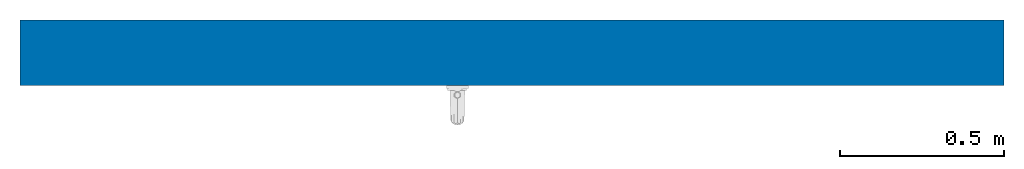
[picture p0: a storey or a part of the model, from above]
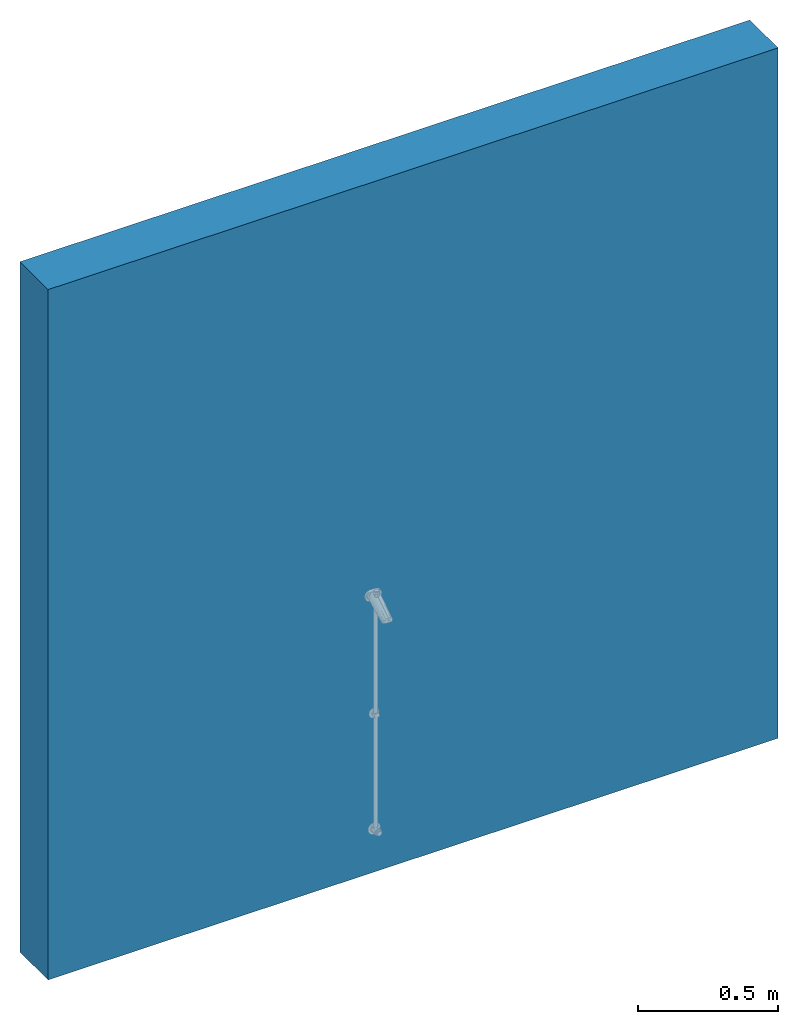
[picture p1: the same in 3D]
Properties of the parts of a building model (IFC2X3)

# File
Description: ViewDefinition [CoordinationView]
File name: Project Number
Time: 2016-08-02T11:35:12
Written by: Autodesk Revit Architecture 2011 - 1.0
Made in: 20100326_1700(x64)

# IfcProject, Project Number
Phase: Project Status

# IfcSite, Default
RefLatitude: 42, 21, 30, 344238; RefLongitude: -71, -3, -35, -194702; RefElevation: 0 mm

# IfcBuilding
Pset_BuildingCommon - NumberOfStoreys: 1
PSet_Revit_Other - Project Issue Date: Issue Date; Project Status: Project Status; Client Name: Owner; Project Address: Enter address here; Project Name: Project Name; Project Number: Project Number

# IfcBuildingStorey, Level 1
Elevation: 0 mm
PSet_Revit_Identity Data - Name: Level 1
PSet_Revit_Constraints - Elevation: 0 mm
PSet_Revit_Type_Graphics - Line Weight: 1; Color: 0; Line Pattern: Centre; Symbol: M_Level Head - Circle; Symbol at End 1 Default: no; Symbol at End 2 Default: yes
PSet_Revit_Type_Constraints - Elevation Base: 0
PSet_Revit_Type_Dimensions - Automatic Room Computation Height: no; Computation Height: 1200 mm

# IfcBuildingElementProxy: Type 1, 714000:Type 1:Type 1:158573
In: Level 1
PSet_Revit_Constraints - Level: Level 1; Elevation: 174.5 mm
PSet_Revit_Mechanical - System Type: Domestic Hot Water; System Name: Default Domestic Hot Water (Polantis_Production)
PSet_Revit_Identity Data - Mark: 9
PSet_Revit_Phasing - Phase Created: New Construction
PSet_Revit_Type_Identity Data - URL: www.delabie.fr; Type Comments: Ensemble de douche temporisé; Technologie: Temporisée; Référence: 714000; Raccordement: M1/2"; Model: SPORTING; Manufacturer: DELABIE; Lien notice d'installation: www.delabie.fr/produits/714000; Lien fiche produit: www.delabie.fr/produits/714000; Lien certification: www.delabie.fr/produits/714000; Lien CCTP: www.delabie.fr/produits/714000; Hauteur: 1015 mm; Finition: Laiton massif chromé; Famille de produits: Douche; Débit l/s: 0.10 l/s à 3 bar; Débit l/min: 6 l/min à 3 bar; Description: DELABIE, fabricant français, est le leader européen de l'équipement sanitaire pour les établissements recevant du public. Robinetteries, solutions pour personnes à mobilité réduite, appareils sanitaires, destinés aux écoles, lieux de loisirs, bureaux, hôpitaux, aéroports, ...; Descriptif: Ensemble de douche temporisé à poser en applique : Colonne de liaison Ø 16 et collier renforcés. Robinet temporisé SPORTING M1/2" pour alimentation par le haut en eau mitigée. Déclenchement souple. Temporisation ~30 sec. Débit 6 l/min à 3 bar. Pomme de douche chromée, inviolable à diffuseur antitartre avec régulateur automatique de débit. Bouton amorceur. Fixations par vis inox fournies. Corps en laiton massif chromé. Clapet antiretour et filtre intégrés.
PSet_Revit_Type_Dimensions - Radius: 10.3 mm

# IfcWallStandardCase: Basic Wall:Generic - 200mm:398, Basic Wall:Generic - 200mm:127590
In: Level 1
Material: Default Wall 200 mm
Pset_WallCommon - Reference: Basic Wall:Generic - 200mm; LoadBearing: no; ExtendToStructure: no; IsExternal: yes
PSet_Revit_Constraints - Location Line: 0; Base Constraint: Level 1; Base Offset: 0 mm; Base is Attached: no; Base Extension Distance: 0 mm; Unconnected Height: 3000 mm; Top Offset: 0 mm; Top is Attached: no; Top Extension Distance: 0 mm; Room Bounding: yes; Related to Mass: no
PSet_Revit_Phasing - Phase Created: New Construction
PSet_Revit_Structural - Structural Usage: 0
PSet_Revit_Dimensions - Length: 3000 mm; Area: 9000000 mm2; Volume: 1800000000 mm3
PSet_Revit_Type_Construction - Wrapping at Inserts: 0; Wrapping at Ends: 0; Width: 200 mm; Function: 1
PSet_Revit_Type_Graphics - Coarse Scale Fill Color: 0
